VERSION 5.7 ;
  NOWIREEXTENSIONATPIN ON ;
  DIVIDERCHAR "/" ;
  BUSBITCHARS "[]" ;
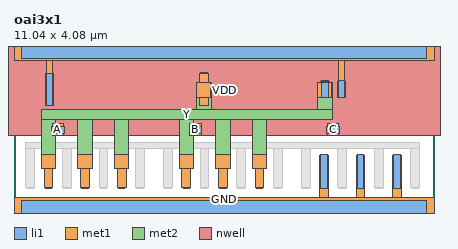
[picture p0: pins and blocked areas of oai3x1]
MACRO oai3x1
  CLASS BLOCK ;
  FOREIGN oai3x1 ;
  ORIGIN 0.000 0.000 ;
  SIZE 11.040 BY 4.080 ;
  PIN A
    ANTENNAGATEAREA 0.882000 ;
    PORT
      LAYER li1 ;
        RECT 0.985 1.930 1.315 2.120 ;
      LAYER met1 ;
        RECT 1.000 1.870 1.300 2.190 ;
    END
  END A
  PIN B
    ANTENNAGATEAREA 0.882000 ;
    PORT
      LAYER li1 ;
        RECT 4.605 1.930 4.935 2.120 ;
      LAYER met1 ;
        RECT 4.620 1.870 4.920 2.190 ;
    END
  END B
  PIN C
    ANTENNAGATEAREA 0.819000 ;
    PORT
      LAYER li1 ;
        RECT 8.225 1.930 8.555 2.120 ;
      LAYER met1 ;
        RECT 8.240 1.870 8.540 2.190 ;
    END
  END C
  PIN Y
    ANTENNADIFFAREA 2.028600 ;
    PORT
      LAYER li1 ;
        RECT 4.905 2.660 5.075 3.540 ;
        RECT 8.085 2.870 8.255 3.330 ;
        RECT 0.825 0.490 0.995 1.370 ;
        RECT 1.785 0.490 1.955 1.370 ;
        RECT 2.745 0.490 2.915 1.370 ;
        RECT 4.445 0.490 4.615 1.370 ;
        RECT 5.405 0.490 5.575 1.370 ;
        RECT 6.365 0.490 6.535 1.370 ;
      LAYER met1 ;
        RECT 4.875 3.260 5.105 3.520 ;
        RECT 8.055 3.260 8.285 3.310 ;
        RECT 4.810 2.880 5.170 3.260 ;
        RECT 7.990 2.880 8.350 3.260 ;
        RECT 4.875 2.680 5.105 2.880 ;
        RECT 0.720 1.010 1.100 1.390 ;
        RECT 1.680 1.010 2.060 1.390 ;
        RECT 2.640 1.010 3.020 1.390 ;
        RECT 4.340 1.010 4.720 1.390 ;
        RECT 5.300 1.010 5.680 1.390 ;
        RECT 6.260 1.010 6.640 1.390 ;
        RECT 0.795 0.510 1.025 1.010 ;
        RECT 1.755 0.510 1.985 1.010 ;
        RECT 2.715 0.510 2.945 1.010 ;
        RECT 4.415 0.510 4.645 1.010 ;
        RECT 5.375 0.510 5.605 1.010 ;
        RECT 6.335 0.510 6.565 1.010 ;
      LAYER met2 ;
        RECT 4.800 2.560 5.180 3.260 ;
        RECT 7.980 2.560 8.360 3.260 ;
        RECT 0.720 2.300 8.360 2.560 ;
        RECT 0.720 1.010 1.100 2.300 ;
        RECT 1.680 1.010 2.060 2.300 ;
        RECT 2.640 1.010 3.020 2.300 ;
        RECT 4.340 1.010 4.720 2.300 ;
        RECT 5.300 1.010 5.680 2.300 ;
        RECT 6.260 1.010 6.640 2.300 ;
    END
  END Y
  PIN VDD
    ANTENNADIFFAREA 3.462600 ;
    PORT
      LAYER nwell ;
        RECT -0.230 1.870 11.270 4.410 ;
      LAYER li1 ;
        RECT 0.210 3.915 10.830 4.245 ;
        RECT 0.845 2.660 1.015 3.540 ;
        RECT 8.525 2.870 8.695 3.330 ;
      LAYER met1 ;
        RECT 0.000 3.840 11.040 4.320 ;
        RECT 0.845 3.520 1.015 3.840 ;
        RECT 0.815 2.680 1.045 3.520 ;
        RECT 8.525 3.310 8.695 3.840 ;
        RECT 8.495 2.890 8.725 3.310 ;
    END
  END VDD
  PIN GND
    ANTENNADIFFAREA 3.928800 ;
    PORT
      LAYER li1 ;
        RECT 8.065 0.490 8.235 1.370 ;
        RECT 9.025 0.490 9.195 1.370 ;
        RECT 9.985 0.490 10.155 1.370 ;
        RECT 0.210 -0.165 10.830 0.165 ;
      LAYER met1 ;
        RECT 8.035 0.240 8.265 1.350 ;
        RECT 8.995 0.240 9.225 1.350 ;
        RECT 9.955 0.240 10.185 1.350 ;
        RECT 0.000 -0.240 11.040 0.240 ;
    END
  END GND
  OBS
      LAYER li1 ;
        RECT 1.285 2.660 1.455 3.540 ;
        RECT 4.465 2.660 4.635 3.540 ;
        RECT 0.345 0.490 0.515 1.370 ;
        RECT 1.305 0.490 1.475 1.370 ;
        RECT 2.265 0.490 2.435 1.370 ;
        RECT 3.225 0.490 3.395 1.370 ;
        RECT 3.965 0.490 4.135 1.370 ;
        RECT 4.925 0.490 5.095 1.370 ;
        RECT 5.885 0.490 6.055 1.370 ;
        RECT 6.845 0.490 7.015 1.370 ;
        RECT 7.585 0.490 7.755 1.370 ;
        RECT 8.545 0.490 8.715 1.370 ;
        RECT 9.505 0.490 9.675 1.370 ;
        RECT 10.465 0.490 10.635 1.370 ;
      LAYER met1 ;
        RECT 1.255 3.200 1.485 3.520 ;
        RECT 4.435 3.200 4.665 3.520 ;
        RECT 1.255 3.000 4.665 3.200 ;
        RECT 1.255 2.680 1.485 3.000 ;
        RECT 4.435 2.680 4.665 3.000 ;
        RECT 0.315 1.540 10.665 1.690 ;
        RECT 0.315 0.510 0.545 1.540 ;
        RECT 1.275 0.510 1.505 1.540 ;
        RECT 2.235 0.510 2.465 1.540 ;
        RECT 3.195 0.510 3.425 1.540 ;
        RECT 3.935 0.510 4.165 1.540 ;
        RECT 4.895 0.510 5.125 1.540 ;
        RECT 5.855 0.510 6.085 1.540 ;
        RECT 6.815 0.510 7.045 1.540 ;
        RECT 7.555 0.510 7.785 1.540 ;
        RECT 8.515 0.510 8.745 1.540 ;
        RECT 9.475 0.510 9.705 1.540 ;
        RECT 10.435 0.510 10.665 1.540 ;
  END
END oai3x1
END LIBRARY

